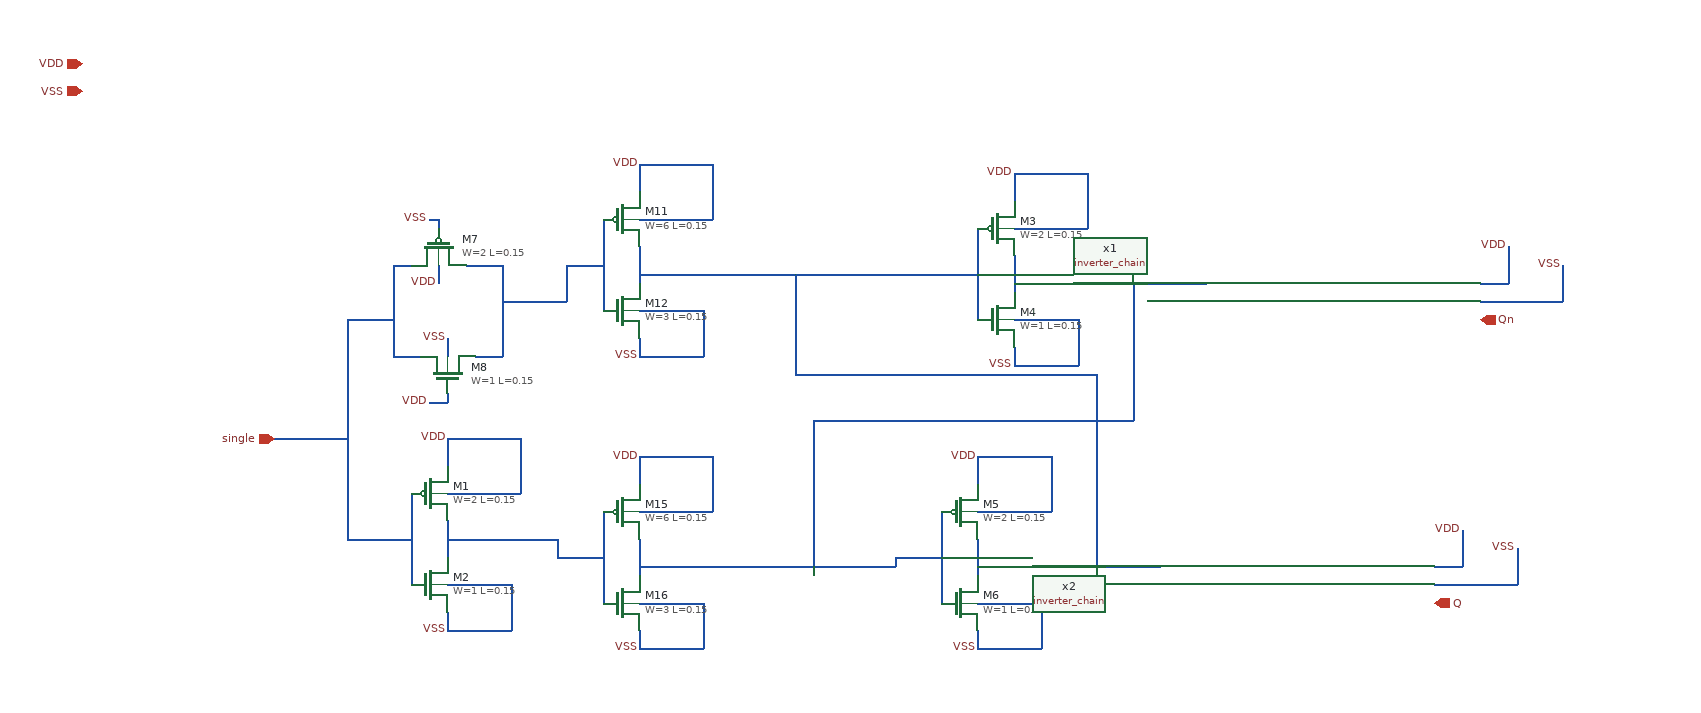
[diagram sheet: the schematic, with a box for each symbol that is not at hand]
v {xschem version=3.4.5 file_version=1.2
}
G {}
K {}
V {}
S {}
E {}
N 10 170 10 210 {
lab=#net1}
N -30 140 -30 240 {
lab=single}
N -30 140 -30 240 {
lab=single}
N 10 80 10 110 {
lab=VDD}
N 10 140 90 140 {
lab=VDD}
N 90 80 90 140 {
lab=VDD}
N 10 80 90 80 {
lab=VDD}
N 10 240 80 240 {
lab=VSS}
N 80 240 80 270 {
lab=VSS}
N 80 270 80 290 {
lab=VSS}
N 10 290 80 290 {
lab=VSS}
N 10 270 10 290 {
lab=VSS}
N -80 190 -30 190 {
lab=single}
N 630 -120 630 -80 {
lab=#net2}
N 590 -150 590 -50 {
lab=#net3}
N 590 -150 590 -50 {
lab=#net3}
N 630 -210 630 -180 {
lab=VDD}
N 630 -150 710 -150 {
lab=VDD}
N 710 -210 710 -150 {
lab=VDD}
N 630 -210 710 -210 {
lab=VDD}
N 630 -50 700 -50 {
lab=VSS}
N 700 -50 700 -20 {
lab=VSS}
N 700 -20 700 0 {
lab=VSS}
N 630 0 700 0 {
lab=VSS}
N 630 -20 630 0 {
lab=VSS}
N 540 -100 590 -100 {
lab=#net3}
N 630 -90 770 -90 {
lab=#net2}
N 590 190 590 230 {
lab=#net3}
N 550 160 550 260 {
lab=#net2}
N 550 160 550 260 {
lab=#net2}
N 590 100 590 130 {
lab=VDD}
N 590 160 670 160 {
lab=VDD}
N 670 100 670 160 {
lab=VDD}
N 590 100 670 100 {
lab=VDD}
N 590 260 660 260 {
lab=VSS}
N 660 260 660 290 {
lab=VSS}
N 660 290 660 310 {
lab=VSS}
N 590 310 660 310 {
lab=VSS}
N 590 290 590 310 {
lab=VSS}
N 500 210 550 210 {
lab=#net2}
N 590 220 730 220 {
lab=#net3}
N 730 220 790 220 {
lab=#net3}
N 770 -90 840 -90 {
lab=#net2}
N -10 -160 0 -160 {
lab=VSS}
N 0 -160 0 -150 {
lab=VSS}
N 0 -110 -0 -90 {
lab=VDD}
N 10 -30 10 -10 {
lab=VSS}
N 30 -110 70 -110 {
lab=#net4}
N 70 -110 70 -50 {
lab=#net4}
N 40 -10 70 -10 {
lab=#net4}
N 70 -50 70 -10 {
lab=#net4}
N -50 -10 -20 -10 {
lab=single}
N -50 -110 -50 -10 {
lab=single}
N -50 -110 -30 -110 {
lab=single}
N 400 -100 540 -100 {
lab=#net3}
N 400 220 500 220 {
lab=#net2}
N 500 210 500 220 {
lab=#net2}
N -100 -50 -50 -50 {
lab=single}
N -100 -50 -100 190 {
lab=single}
N -100 190 -80 190 {
lab=single}
N -10 40 10 40 {
lab=VDD}
N 10 30 10 40 {
lab=VDD}
N -180 80 -100 80 {
lab=single}
N 220 -130 220 -90 {
lab=#net3}
N 180 -160 180 -60 {
lab=#net4}
N 180 -160 180 -60 {
lab=#net4}
N 220 -220 220 -190 {
lab=VDD}
N 220 -160 300 -160 {
lab=VDD}
N 300 -220 300 -160 {
lab=VDD}
N 220 -220 300 -220 {
lab=VDD}
N 220 -60 290 -60 {
lab=VSS}
N 290 -60 290 -30 {
lab=VSS}
N 290 -30 290 -10 {
lab=VSS}
N 220 -10 290 -10 {
lab=VSS}
N 220 -30 220 -10 {
lab=VSS}
N 220 -100 400 -100 {
lab=#net3}
N 220 190 220 230 {
lab=#net2}
N 180 160 180 260 {
lab=#net1}
N 180 160 180 260 {
lab=#net1}
N 220 100 220 130 {
lab=VDD}
N 220 160 300 160 {
lab=VDD}
N 300 100 300 160 {
lab=VDD}
N 220 100 300 100 {
lab=VDD}
N 220 260 290 260 {
lab=VSS}
N 290 260 290 290 {
lab=VSS}
N 290 290 290 310 {
lab=VSS}
N 220 310 290 310 {
lab=VSS}
N 220 290 220 310 {
lab=VSS}
N 130 210 180 210 {
lab=#net1}
N 220 220 400 220 {
lab=#net2}
N 70 -70 140 -70 {
lab=#net4}
N 140 -110 140 -70 {
lab=#net4}
N 140 -110 180 -110 {
lab=#net4}
N 10 190 130 190 {
lab=#net1}
N 130 190 130 210 {
lab=#net1}
N 390 -100 390 10 {
lab=#net3}
N 390 10 720 10 {
lab=#net3}
N 720 10 720 220 {
lab=#net3}
N 410 60 410 220 {
lab=#net2}
N 410 60 760 60 {
lab=#net2}
N 760 -90 760 60 {
lab=#net2}
N 1140 -90 1170 -90 {
lab=VDD}
N 1170 -130 1170 -90 {
lab=VDD}
N 1140 -70 1230 -70 {}
N 1230 -110 1230 -70 {}
N 1090 220 1120 220 {
lab=VDD}
N 1120 180 1120 220 {
lab=VDD}
N 1090 240 1180 240 {}
N 1180 200 1180 240 {}
C {sky130_fd_pr/pfet_01v8.sym} -10 140 0 0 {name=M1
L=0.15
W=2
nf=1
mult=1
ad="'int((nf+1)/2) * W/nf * 0.29'" 
pd="'2*int((nf+1)/2) * (W/nf + 0.29)'"
as="'int((nf+2)/2) * W/nf * 0.29'" 
ps="'2*int((nf+2)/2) * (W/nf + 0.29)'"
nrd="'0.29 / W'" nrs="'0.29 / W'"
sa=0 sb=0 sd=0
model=pfet_01v8
spiceprefix=X
}
C {sky130_fd_pr/nfet_01v8.sym} -10 240 0 0 {name=M2
L=0.15
W=1
nf=1 
mult=1
ad="'int((nf+1)/2) * W/nf * 0.29'" 
pd="'2*int((nf+1)/2) * (W/nf + 0.29)'"
as="'int((nf+2)/2) * W/nf * 0.29'" 
ps="'2*int((nf+2)/2) * (W/nf + 0.29)'"
nrd="'0.29 / W'" nrs="'0.29 / W'"
sa=0 sb=0 sd=0
model=nfet_01v8
spiceprefix=X
}
C {devices/lab_wire.sym} 10 80 0 0 {name=p3 sig_type=std_logic lab=VDD}
C {devices/lab_wire.sym} 10 290 0 0 {name=p4 sig_type=std_logic lab=VSS}
C {devices/ipin.sym} -180 80 0 0 {name=p9 lab=single
}
C {sky130_fd_pr/pfet_01v8.sym} 610 -150 0 0 {name=M3
L=0.15
W=2
nf=1
mult=1
ad="'int((nf+1)/2) * W/nf * 0.29'" 
pd="'2*int((nf+1)/2) * (W/nf + 0.29)'"
as="'int((nf+2)/2) * W/nf * 0.29'" 
ps="'2*int((nf+2)/2) * (W/nf + 0.29)'"
nrd="'0.29 / W'" nrs="'0.29 / W'"
sa=0 sb=0 sd=0
model=pfet_01v8
spiceprefix=X
}
C {sky130_fd_pr/nfet_01v8.sym} 610 -50 0 0 {name=M4
L=0.15
W=1
nf=1 
mult=1
ad="'int((nf+1)/2) * W/nf * 0.29'" 
pd="'2*int((nf+1)/2) * (W/nf + 0.29)'"
as="'int((nf+2)/2) * W/nf * 0.29'" 
ps="'2*int((nf+2)/2) * (W/nf + 0.29)'"
nrd="'0.29 / W'" nrs="'0.29 / W'"
sa=0 sb=0 sd=0
model=nfet_01v8
spiceprefix=X
}
C {devices/lab_wire.sym} 630 -210 0 0 {name=p1 sig_type=std_logic lab=VDD}
C {devices/lab_wire.sym} 630 0 0 0 {name=p2 sig_type=std_logic lab=VSS}
C {sky130_fd_pr/pfet_01v8.sym} 570 160 0 0 {name=M5
L=0.15
W=2
nf=1
mult=1
ad="'int((nf+1)/2) * W/nf * 0.29'" 
pd="'2*int((nf+1)/2) * (W/nf + 0.29)'"
as="'int((nf+2)/2) * W/nf * 0.29'" 
ps="'2*int((nf+2)/2) * (W/nf + 0.29)'"
nrd="'0.29 / W'" nrs="'0.29 / W'"
sa=0 sb=0 sd=0
model=pfet_01v8
spiceprefix=X
}
C {sky130_fd_pr/nfet_01v8.sym} 570 260 0 0 {name=M6
L=0.15
W=1
nf=1 
mult=1
ad="'int((nf+1)/2) * W/nf * 0.29'" 
pd="'2*int((nf+1)/2) * (W/nf + 0.29)'"
as="'int((nf+2)/2) * W/nf * 0.29'" 
ps="'2*int((nf+2)/2) * (W/nf + 0.29)'"
nrd="'0.29 / W'" nrs="'0.29 / W'"
sa=0 sb=0 sd=0
model=nfet_01v8
spiceprefix=X
}
C {devices/lab_wire.sym} 590 100 0 0 {name=p5 sig_type=std_logic lab=VDD}
C {devices/lab_wire.sym} 590 310 0 0 {name=p6 sig_type=std_logic lab=VSS}
C {sky130_fd_pr/pfet_01v8.sym} 0 -130 1 0 {name=M7
L=0.15
W=2
nf=1
mult=1
ad="'int((nf+1)/2) * W/nf * 0.29'" 
pd="'2*int((nf+1)/2) * (W/nf + 0.29)'"
as="'int((nf+2)/2) * W/nf * 0.29'" 
ps="'2*int((nf+2)/2) * (W/nf + 0.29)'"
nrd="'0.29 / W'" nrs="'0.29 / W'"
sa=0 sb=0 sd=0
model=pfet_01v8
spiceprefix=X
}
C {sky130_fd_pr/nfet_01v8.sym} 10 10 3 0 {name=M8
L=0.15
W=1
nf=1 
mult=1
ad="'int((nf+1)/2) * W/nf * 0.29'" 
pd="'2*int((nf+1)/2) * (W/nf + 0.29)'"
as="'int((nf+2)/2) * W/nf * 0.29'" 
ps="'2*int((nf+2)/2) * (W/nf + 0.29)'"
nrd="'0.29 / W'" nrs="'0.29 / W'"
sa=0 sb=0 sd=0
model=nfet_01v8
spiceprefix=X
}
C {devices/lab_wire.sym} -10 40 0 0 {name=p7 sig_type=std_logic lab=VDD}
C {devices/lab_wire.sym} 0 -90 0 0 {name=p8 sig_type=std_logic lab=VDD}
C {devices/lab_wire.sym} 10 -30 0 0 {name=p10 sig_type=std_logic lab=VSS}
C {devices/lab_wire.sym} -10 -160 0 0 {name=p11 sig_type=std_logic lab=VSS}
C {devices/opin.sym} 1140 -50 0 0 {name=p12 lab=Qn}
C {devices/opin.sym} 1090 260 0 0 {name=p13 lab=Q}
C {sky130_fd_pr/pfet_01v8.sym} 200 -160 0 0 {name=M11
L=0.15
W=6
nf=4
mult=1
ad="'int((nf+1)/2) * W/nf * 0.29'" 
pd="'2*int((nf+1)/2) * (W/nf + 0.29)'"
as="'int((nf+2)/2) * W/nf * 0.29'" 
ps="'2*int((nf+2)/2) * (W/nf + 0.29)'"
nrd="'0.29 / W'" nrs="'0.29 / W'"
sa=0 sb=0 sd=0
model=pfet_01v8
spiceprefix=X
}
C {sky130_fd_pr/nfet_01v8.sym} 200 -60 0 0 {name=M12
L=0.15
W=3
nf=2 
mult=1
ad="'int((nf+1)/2) * W/nf * 0.29'" 
pd="'2*int((nf+1)/2) * (W/nf + 0.29)'"
as="'int((nf+2)/2) * W/nf * 0.29'" 
ps="'2*int((nf+2)/2) * (W/nf + 0.29)'"
nrd="'0.29 / W'" nrs="'0.29 / W'"
sa=0 sb=0 sd=0
model=nfet_01v8
spiceprefix=X
}
C {devices/lab_wire.sym} 220 -220 0 0 {name=p16 sig_type=std_logic lab=VDD}
C {devices/lab_wire.sym} 220 -10 0 0 {name=p17 sig_type=std_logic lab=VSS}
C {sky130_fd_pr/pfet_01v8.sym} 200 160 0 0 {name=M15
L=0.15
W=6
nf=4
mult=1
ad="'int((nf+1)/2) * W/nf * 0.29'" 
pd="'2*int((nf+1)/2) * (W/nf + 0.29)'"
as="'int((nf+2)/2) * W/nf * 0.29'" 
ps="'2*int((nf+2)/2) * (W/nf + 0.29)'"
nrd="'0.29 / W'" nrs="'0.29 / W'"
sa=0 sb=0 sd=0
model=pfet_01v8
spiceprefix=X
}
C {sky130_fd_pr/nfet_01v8.sym} 200 260 0 0 {name=M16
L=0.15
W=3
nf=2 
mult=1
ad="'int((nf+1)/2) * W/nf * 0.29'" 
pd="'2*int((nf+1)/2) * (W/nf + 0.29)'"
as="'int((nf+2)/2) * W/nf * 0.29'" 
ps="'2*int((nf+2)/2) * (W/nf + 0.29)'"
nrd="'0.29 / W'" nrs="'0.29 / W'"
sa=0 sb=0 sd=0
model=nfet_01v8
spiceprefix=X
}
C {devices/lab_wire.sym} 220 100 0 0 {name=p20 sig_type=std_logic lab=VDD}
C {devices/lab_wire.sym} 220 310 0 0 {name=p21 sig_type=std_logic lab=VSS}
C {devices/iopin.sym} -390 -330 0 0 {name=p22 lab=VDD


}
C {devices/iopin.sym} -390 -300 0 0 {name=p23 lab=VSS


}
C {inverter_chain.sym} 990 -70 0 0 {name=x1}
C {inverter_chain.sym} 940 240 0 0 {name=x2}
C {devices/lab_wire.sym} 1170 -130 0 0 {name=p14 sig_type=std_logic lab=VDD}
C {devices/lab_wire.sym} 1230 -110 0 0 {name=p15 sig_type=std_logic lab=VSS}
C {devices/lab_wire.sym} 1120 180 0 0 {name=p18 sig_type=std_logic lab=VDD}
C {devices/lab_wire.sym} 1180 200 0 0 {name=p19 sig_type=std_logic lab=VSS}
